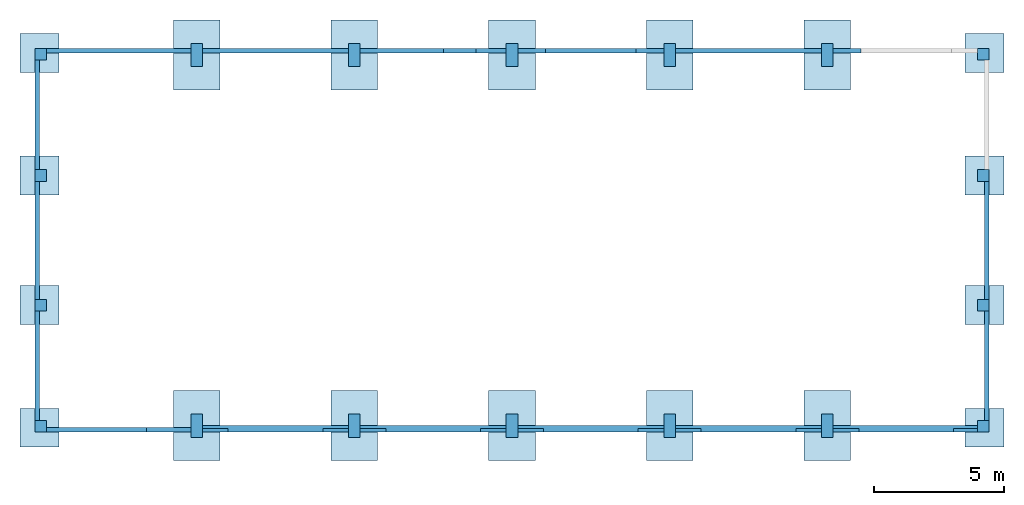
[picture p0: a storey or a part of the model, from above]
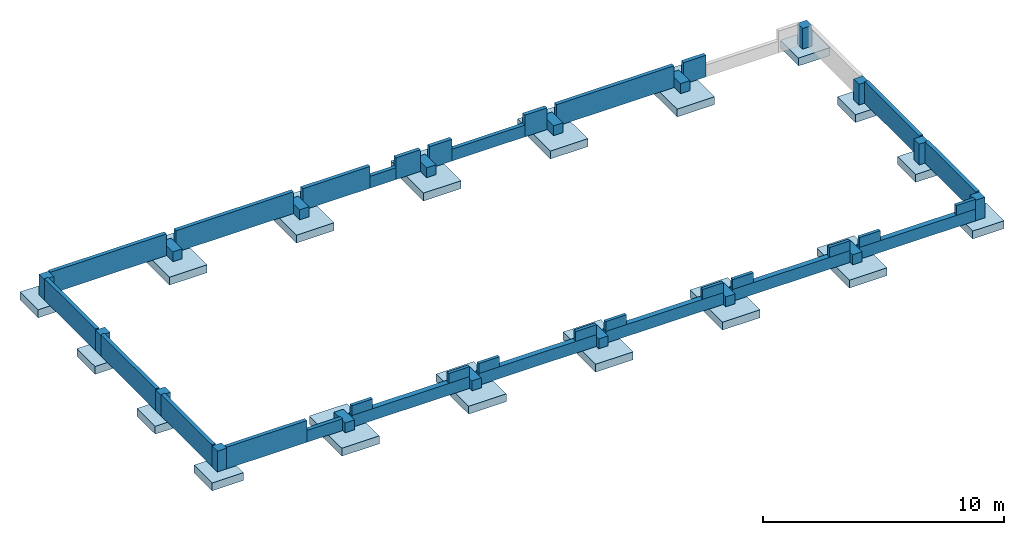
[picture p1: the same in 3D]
Properties of the parts of a building model (IFC2X3)

# File
Description: no view
File name: D:\PATRYK_ud\PR_1012_Wadowice\03 IFC\PR-1012-WADOWICE_szalunki_v2.ifc
Time: 2025-11-19T12:53:41
Organization: No Organization
Written by: EDMsix Version 2.0100.09 Sep 7 2016
Made in: Allplan 2021.1 11.10.2023 - 17:45:04

# IfcBuildingStorey, Fundamenty
In: Szalunki
Elevation: 0 m

# IfcFooting (36)
In: Fundamenty
PredefinedType: PAD_FOOTING
AllplanAttributes - Jednostka: m3; Nazwa obiektu: Stopa fundamentowa
Pset_FootingCommon - Status: Nowo projektowane
Name | ID_komponentu_Allright
 | 0101EFu0000000002 | AllplanAttributes - Skos z lewej: 100; Skos z prawej: 100; Skos z przodu: 100; Skos z tyłu: 100; Pset_FootingCommon - LoadBearing: no
 | 0101EFu0000000013 | AllplanAttributes - Skos z lewej: 100; Skos z prawej: 100; Skos z przodu: 100; Skos z tyłu: 100; Pset_FootingCommon - LoadBearing: no
 | 0101EFu0000000014 | AllplanAttributes - Skos z lewej: 100; Skos z prawej: 100; Skos z przodu: 100; Skos z tyłu: 100; Pset_FootingCommon - LoadBearing: no
 | 0101EFu0000000015 | AllplanAttributes - Skos z lewej: 100; Skos z prawej: 100; Skos z przodu: 100; Skos z tyłu: 100; Pset_FootingCommon - LoadBearing: no
 | 0101EFu0000000016 | AllplanAttributes - Skos z lewej: 100; Skos z prawej: 100; Skos z przodu: 100; Skos z tyłu: 100; Pset_FootingCommon - LoadBearing: no
 | 0101EFu0000000022 | AllplanAttributes - Skos z lewej: 100; Skos z prawej: 100; Skos z przodu: 100; Skos z tyłu: 100; Pset_FootingCommon - LoadBearing: no
 | 0101EFu0000000021 | AllplanAttributes - Skos z lewej: 100; Skos z prawej: 100; Skos z przodu: 100; Skos z tyłu: 100; Pset_FootingCommon - LoadBearing: no
 | 0101EFu0000000020 | AllplanAttributes - Skos z lewej: 100; Skos z prawej: 100; Skos z przodu: 100; Skos z tyłu: 100; Pset_FootingCommon - LoadBearing: no
 | 0101EFu0000000019 | AllplanAttributes - Skos z lewej: 100; Skos z prawej: 100; Skos z przodu: 100; Skos z tyłu: 100; Pset_FootingCommon - LoadBearing: no
 | 0101EFu0000000018 | AllplanAttributes - Skos z lewej: 100; Skos z prawej: 100; Skos z przodu: 100; Skos z tyłu: 100; Pset_FootingCommon - LoadBearing: no
 | 0101EFu0000000033 | Pset_FootingCommon - LoadBearing: no
 | 0101EFu0000000046 | Pset_FootingCommon - LoadBearing: no
 | 0101EFu0000000047 | Pset_FootingCommon - LoadBearing: no
 | 0101EFu0000000048 | Pset_FootingCommon - LoadBearing: no
 | 0101EFu0000000054 | Pset_FootingCommon - LoadBearing: no
 | 0101EFu0000000053 | Pset_FootingCommon - LoadBearing: no
 | 0101EFu0000000052 | Pset_FootingCommon - LoadBearing: no
 | 0101EFu0000000051 | Pset_FootingCommon - LoadBearing: no
 | 0102EFu0000000002
 | 0102EFu0000000005
 | 0102EFu0000000006
 | 0102EFu0000000007
 | 0102EFu0000000008
 | 0102EFu0000000014
 | 0102EFu0000000013
 | 0102EFu0000000012
 | 0102EFu0000000011
 | 0102EFu0000000010
 | 0102EFu0000000037
 | 0102EFu0000000038
 | 0102EFu0000000039
 | 0102EFu0000000025
 | 0102EFu0000000044
 | 0102EFu0000000043
 | 0102EFu0000000042
 | 0102EFu0000000045

# IfcWallStandardCase (35)
In: Fundamenty
AllplanAttributes - Nazwa obiektu: Belka Podwalinowa; Jednostka: m3; Object Layer Attributes #1, Renowacja: Nowo projektowane; Object Layer Attributes #1, Typ_robót: Roboty murarskie; Object Layer Attributes #1, Nazwa obiektu: Belka Podwalinowa; Object Layer Attributes #1, Jednostka: m3
Name | Material | ID_komponentu_Allright | Object Layer Attributes #1, ID_komponentu_Allright
 | layer 0.18 m | 0103HWa0000000007 | 0103Śc.0000000008
 | layer 0.18 m | 0103HWa0000000027 | 0103Śc.0000000029
 | layer 0.18 m | 0103HWa0000000021 | 0103Śc.0000000023
 | layer 0.18 m | 0103HWa0000000098 | 0103Śc.0000000100
 | layer 0.18 m | 0103HWa0000000069 | 0103Śc.0000000071
 | layer 0.18 m | 0103HWa0000000296 | 0103Śc.0000000300
 | layer 0.18 m | 0103HWa0000000425 | 0103Śc.0000000427
 | layer 0.18 m | 0103HWa0000000439 | 0103Śc.0000000441
 | layer 0.18 m | 0103HWa0000000442 | 0103Śc.0000000444
 | layer 0.18 m | 0103HWa0000000436 | 0103Śc.0000000438
 | layer 0.18 m | 0103HWa0000000193 | 0103Śc.0000000195
 | layer 0.18 m | 0103HWa0000000190 | 0103Śc.0000000192
 | layer 0.18 m | 0103HWa0000000188 | 0103Śc.0000000196
 | layer 0.18 m | 0103HWa0000000177 | 0103Śc.0000000179
 | layer 0.18 m | 0103HWa0000000151 | 0103Śc.0000000156
 | layer 0.18 m | 0103HWa0000000153 | 0103Śc.0000000155
 | layer 0.18 m | 0103HWa0000000292 | 0103Śc.0000000298
 | layer 0.18 m | 0103HWa0000000431 | 0103Śc.0000000433
 | layer 0.18 m | 0103HWa0000000016 | 0103Śc.0000000018
 | layer 0.18 m | 0103HWa0000000392 | 0103Śc.0000000394
 | layer 0.25 m | 0103HWa0000000235 | 0103Śc.0000000243
 | layer 0.15 m | 0103HWa0000000240 | 0103Śc.0000000242
 | layer 0.15 m | 0103HWa0000000237 | 0103Śc.0000000239
 | layer 0.25 m | 0103HWa0000022757 | 0103Śc.0000022759
 | layer 0.15 m | 0103HWa0000022763 | 0103Śc.0000022765
 | layer 0.15 m | 0103HWa0000022760 | 0103Śc.0000022762
 | layer 0.25 m | 0103HWa0000022778 | 0103Śc.0000022780
 | layer 0.15 m | 0103HWa0000022781 | 0103Śc.0000022783
 | layer 0.15 m | 0103HWa0000022784 | 0103Śc.0000022786
 | layer 0.25 m | 0103HWa0000022788 | 0103Śc.0000022790
 | layer 0.15 m | 0103HWa0000022791 | 0103Śc.0000022793
 | layer 0.15 m | 0103HWa0000022794 | 0103Śc.0000022796
 | layer 0.25 m | 0103HWa0000022797 | 0103Śc.0000022799
 | layer 0.15 m | 0103HWa0000022800 | 0103Śc.0000022802
 | layer 0.15 m | 0103HWa0000022803 | 0103Śc.0000022805
